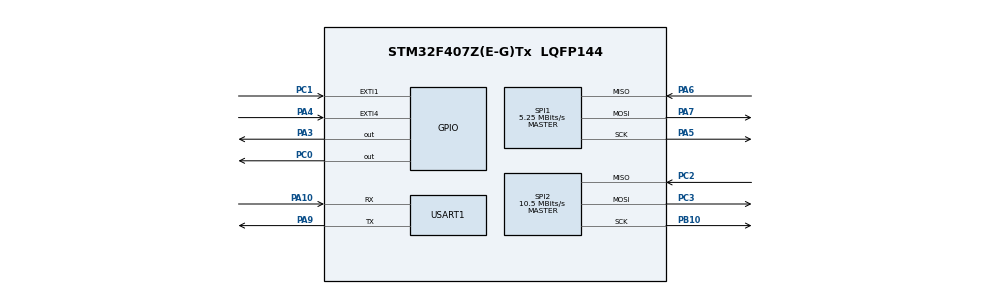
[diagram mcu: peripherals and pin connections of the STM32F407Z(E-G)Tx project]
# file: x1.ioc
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FREERTOS.BinarySemaphores01=xa1,Dynamic,NULL;xa2,Dynamic,NULL
FREERTOS.Tasks01=x1Task,24,128,StartTask01,Default,NULL,Dynamic,NULL,NULL;x2Task,25,128,StartTask02,Default,NULL,Dynamic,NULL,NULL;x3Task,26,128,StartTask03,Default,NULL,Dynamic,NULL,NULL
Mcu.Family=STM32F4
Mcu.Name=STM32F407Z(E-G)Tx
Mcu.Package=LQFP144
NVIC.EXTI1_IRQn=true\:5\:0\:false\:false\:true\:true\:true\:true
NVIC.EXTI4_IRQn=true\:5\:0\:false\:false\:true\:true\:true\:true
NVIC.PriorityGroup=NVIC_PRIORITYGROUP_4
NVIC.TIM4_IRQn=true\:5\:0\:false\:false\:true\:true\:true\:true
NVIC.TIM7_IRQn=true\:0\:0\:false\:false\:true\:false\:false\:true
NVIC.TimeBase=TIM7_IRQn
NVIC.TimeBaseIP=TIM7
PA10.Mode=Asynchronous
PA10.Signal=USART1_RX
PA3.GPIO_Speed=GPIO_SPEED_FREQ_VERY_HIGH
PA3.Signal=GPIO_Output
PA4.GPIO_ModeDefaultEXTI=GPIO_MODE_IT_FALLING
PA4.Signal=GPXTI4
PA5.Mode=Full_Duplex_Master
PA5.Signal=SPI1_SCK
PA6.Mode=Full_Duplex_Master
PA6.Signal=SPI1_MISO
PA7.Mode=Full_Duplex_Master
PA7.Signal=SPI1_MOSI
PA9.Mode=Asynchronous
PA9.Signal=USART1_TX
PB10.Mode=Full_Duplex_Master
PB10.Signal=SPI2_SCK
PC0.GPIO_Speed=GPIO_SPEED_FREQ_VERY_HIGH
PC0.Signal=GPIO_Output
PC1.GPIO_ModeDefaultEXTI=GPIO_MODE_IT_FALLING
PC1.Signal=GPXTI1
PC2.Mode=Full_Duplex_Master
PC2.Signal=SPI2_MISO
PC3.Mode=Full_Duplex_Master
PC3.Signal=SPI2_MOSI
PH0-OSC_IN.Mode=HSE-External-Oscillator
PH0-OSC_IN.Signal=RCC_OSC_IN
PH1-OSC_OUT.Mode=HSE-External-Oscillator
PH1-OSC_OUT.Signal=RCC_OSC_OUT
ProjectManager.HeapSize=0x200
ProjectManager.StackSize=0x400
ProjectManager.TargetToolchain=MDK-ARM V5.27
RCC.48MHZClocksFreq_Value=84000000
RCC.AHBFreq_Value=168000000
RCC.APB1CLKDivider=RCC_HCLK_DIV4
RCC.APB1Freq_Value=42000000
RCC.APB1TimFreq_Value=84000000
RCC.APB2CLKDivider=RCC_HCLK_DIV2
RCC.APB2Freq_Value=84000000
RCC.APB2TimFreq_Value=168000000
RCC.CortexFreq_Value=168000000
RCC.HCLKFreq_Value=168000000
RCC.HSE_VALUE=25000000
RCC.HSI_VALUE=16000000
RCC.LSE_VALUE=32768
RCC.PLLM=8
RCC.PLLN=168
RCC.SYSCLKFreq_VALUE=168000000
RCC.SYSCLKSource=RCC_SYSCLKSOURCE_PLLCLK
RCC.VCOOutputFreq_Value=336000000
SPI1.BaudRatePrescaler=SPI_BAUDRATEPRESCALER_16
SPI1.CalculateBaudRate=5.25 MBits/s
SPI1.Direction=SPI_DIRECTION_2LINES
SPI1.Mode=SPI_MODE_MASTER
SPI1.VirtualType=VM_MASTER
SPI2.BaudRatePrescaler=SPI_BAUDRATEPRESCALER_4
SPI2.CalculateBaudRate=10.5 MBits/s
SPI2.Direction=SPI_DIRECTION_2LINES
SPI2.Mode=SPI_MODE_MASTER
SPI2.VirtualType=VM_MASTER
TIM4.Period=9999
TIM4.Prescaler=8399
USART1.VirtualMode=VM_ASYNC
VP_FREERTOS_VS_CMSIS_V2.Mode=CMSIS_V2
VP_SYS_VS_tim7.Mode=TIM7
VP_TIM4_VS_ClockSourceINT.Mode=Internal
board=custom

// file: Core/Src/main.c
/* USER CODE BEGIN Header */
/**
  ******************************************************************************
  * @file           : main.c
  * @brief          : Main program body
  ******************************************************************************
  * @attention
  *
  * <h2><center>&copy; Copyright (c) 2021 STMicroelectronics.
  * All rights reserved.</center></h2>
  *
  * This software component is licensed by ST under BSD 3-Clause license,
  * the "License"; You may not use this file except in compliance with the
  * License. You may obtain a copy of the License at:
  *                        opensource.org/licenses/BSD-3-Clause
  *
  ******************************************************************************
  */
/* USER CODE END Header */
#include "main.h"
#include "cmsis_os.h"
#include "spi.h"
#include "tim.h"
#include "usart.h"
#include "gpio.h"

/* USER CODE BEGIN Includes */
#include "a7131.h"
/* USER CODE END Includes */

void SystemClock_Config(void);
void MX_FREERTOS_Init(void);

/* USER CODE BEGIN 0 */
int ss=0;
int canRead=0;
int sum=0;
int fputc(int ch,FILE *f)
{
    HAL_UART_Transmit(&huart1,(unsigned char *)&ch,1,2);
		return 0;
}

/* USER CODE END 0 */

int main(void)
{

  /* MCU Configuration--------------------------------------------------------*/

  /* Reset of all peripherals, Initializes the Flash interface and the Systick. */
  HAL_Init();

  /* Configure the system clock */
  SystemClock_Config();

  /* Initialize all configured peripherals */
  MX_GPIO_Init();
  MX_SPI1_Init();
  MX_USART1_UART_Init();
  MX_TIM4_Init();
  MX_SPI2_Init();
  /* USER CODE BEGIN 2 */
	InitA7131();
	InitA71312();
//	HAL_TIM_Base_Start_IT(&htim4);
	WriteFIFO2( 64);
//	int s;
  /* USER CODE END 2 */

  /* Init scheduler */
  osKernelInitialize();  /* Call init function for freertos objects (in freertos.c) */
  MX_FREERTOS_Init();
  /* Start scheduler */
  osKernelStart();

  /* We should never get here as control is now taken by the scheduler */
  /* Infinite loop */
  while (1)
  {

  }
}

void SystemClock_Config(void)
{
  RCC_OscInitTypeDef RCC_OscInitStruct = {0};
  RCC_ClkInitTypeDef RCC_ClkInitStruct = {0};

  /** Configure the main internal regulator output voltage
  */
  __HAL_RCC_PWR_CLK_ENABLE();
  __HAL_PWR_VOLTAGESCALING_CONFIG(PWR_REGULATOR_VOLTAGE_SCALE1);
  /** Initializes the RCC Oscillators according to the specified parameters
  * in the RCC_OscInitTypeDef structure.
  */
  RCC_OscInitStruct.OscillatorType = RCC_OSCILLATORTYPE_HSE;
  RCC_OscInitStruct.HSEState = RCC_HSE_ON;
  RCC_OscInitStruct.PLL.PLLState = RCC_PLL_ON;
  RCC_OscInitStruct.PLL.PLLSource = RCC_PLLSOURCE_HSE;
  RCC_OscInitStruct.PLL.PLLM = 4;
  RCC_OscInitStruct.PLL.PLLN = 168;
  RCC_OscInitStruct.PLL.PLLP = RCC_PLLP_DIV2;
  RCC_OscInitStruct.PLL.PLLQ = 4;
  if (HAL_RCC_OscConfig(&RCC_OscInitStruct) != HAL_OK)
  {
    Error_Handler();
  }
  /** Initializes the CPU, AHB and APB buses clocks
  */
  RCC_ClkInitStruct.ClockType = RCC_CLOCKTYPE_HCLK|RCC_CLOCKTYPE_SYSCLK
                              |RCC_CLOCKTYPE_PCLK1|RCC_CLOCKTYPE_PCLK2;
  RCC_ClkInitStruct.SYSCLKSource = RCC_SYSCLKSOURCE_PLLCLK;
  RCC_ClkInitStruct.AHBCLKDivider = RCC_SYSCLK_DIV1;
  RCC_ClkInitStruct.APB1CLKDivider = RCC_HCLK_DIV4;
  RCC_ClkInitStruct.APB2CLKDivider = RCC_HCLK_DIV2;

  if (HAL_RCC_ClockConfig(&RCC_ClkInitStruct, FLASH_LATENCY_5) != HAL_OK)
  {
    Error_Handler();
  }
}

 /**
  * @brief  Period elapsed callback in non blocking mode
  * @note   This function is called  when TIM7 interrupt took place, inside
  * HAL_TIM_IRQHandler(). It makes a direct call to HAL_IncTick() to increment
  * a global variable "uwTick" used as application time base.
  * @param  htim : TIM handle
  * @retval None
  */
void HAL_TIM_PeriodElapsedCallback(TIM_HandleTypeDef *htim)
{
  if (htim->Instance == TIM7) {
    HAL_IncTick();
  }
}

void Error_Handler(void)
{
  __disable_irq();
  while (1)
  {
  }
}

/************************ (C) COPYRIGHT STMicroelectronics *****END OF FILE****/

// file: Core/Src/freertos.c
/* USER CODE BEGIN Header */
/**
  ******************************************************************************
  * File Name          : freertos.c
  * Description        : Code for freertos applications
  ******************************************************************************
  * @attention
  *
  * <h2><center>&copy; Copyright (c) 2021 STMicroelectronics.
  * All rights reserved.</center></h2>
  *
  * This software component is licensed by ST under Ultimate Liberty license
  * SLA0044, the "License"; You may not use this file except in compliance with
  * the License. You may obtain a copy of the License at:
  *                             www.st.com/SLA0044
  *
  ******************************************************************************
  */
/* USER CODE END Header */

#include "FreeRTOS.h"
#include "task.h"
#include "main.h"
#include "cmsis_os.h"

/* Definitions for x1Task */
osThreadId_t x1TaskHandle;
const osThreadAttr_t x1Task_attributes = {
  .name = "x1Task",
  .priority = (osPriority_t) osPriorityNormal,
  .stack_size = 128 * 4
};
/* Definitions for x2Task */
osThreadId_t x2TaskHandle;
const osThreadAttr_t x2Task_attributes = {
  .name = "x2Task",
  .priority = (osPriority_t) osPriorityNormal1,
  .stack_size = 128 * 4
};
/* Definitions for x3Task */
osThreadId_t x3TaskHandle;
const osThreadAttr_t x3Task_attributes = {
  .name = "x3Task",
  .priority = (osPriority_t) osPriorityLow1,
  .stack_size = 128 * 4
};
/* Definitions for xa1 */
osSemaphoreId_t xa1Handle;
const osSemaphoreAttr_t xa1_attributes = {
  .name = "xa1"
};
/* Definitions for xa2 */
osSemaphoreId_t xa2Handle;
const osSemaphoreAttr_t xa2_attributes = {
  .name = "xa2"
};

void StartTask01(void *argument);
void StartTask02(void *argument);
void StartTask03(void *argument);

void MX_FREERTOS_Init(void); /* (MISRA C 2004 rule 8.1) */

void MX_FREERTOS_Init(void) {

  /* Create the semaphores(s) */
  /* creation of xa1 */
  xa1Handle = osSemaphoreNew(1, 1, &xa1_attributes);

  /* creation of xa2 */
  xa2Handle = osSemaphoreNew(1, 1, &xa2_attributes);

  /* Create the thread(s) */
  /* creation of x1Task */
  x1TaskHandle = osThreadNew(StartTask01, NULL, &x1Task_attributes);

  /* creation of x2Task */
  x2TaskHandle = osThreadNew(StartTask02, NULL, &x2Task_attributes);

  /* creation of x3Task */
  x3TaskHandle = osThreadNew(StartTask03, NULL, &x3Task_attributes);

}

void StartTask01(void *argument)
{
  /* USER CODE BEGIN StartTask01 */
  /* Infinite loop */
  for(;;)
  {
   osSemaphoreAcquire(xa1Handle,1000);
		StrobeCmd(CMD_RX);
			ss++;
  }
  /* USER CODE END StartTask01 */
}

void StartTask02(void *argument)
{
  /* USER CODE BEGIN StartTask02 */
  /* Infinite loop */
  for(;;)
  {
osSemaphoreAcquire(xa2Handle,1000);
StrobeCmd2( CMD_TX );
  }
  /* USER CODE END StartTask02 */
}

void StartTask03(void *argument)
{
  /* USER CODE BEGIN StartTask03 */
  /* Infinite loop */
  for(;;)
  {
		printf("dfdf   %d\n", ss);ss=0;
    osDelay(1000);
  }
  /* USER CODE END StartTask03 */
}

/* USER CODE BEGIN Application */
void HAL_GPIO_EXTI_Callback(uint16_t GPIO_Pin){
    if (GPIO_Pin == GPIO_PIN_4) {
			osSemaphoreRelease(xa1Handle);
		}
	else if (GPIO_Pin == GPIO_PIN_1) {
			osSemaphoreRelease(xa2Handle);
		}
}
/* USER CODE END Application */

/************************ (C) COPYRIGHT STMicroelectronics *****END OF FILE****/
